# Generated by innovus_enablement/scripts/gen_fakeram.py: abstract 128x116 SRAM.
# Geometry is an assumption (see script header), not PDK data.
VERSION 5.8 ;
BUSBITCHARS "[]" ;
DIVIDERCHAR "/" ;

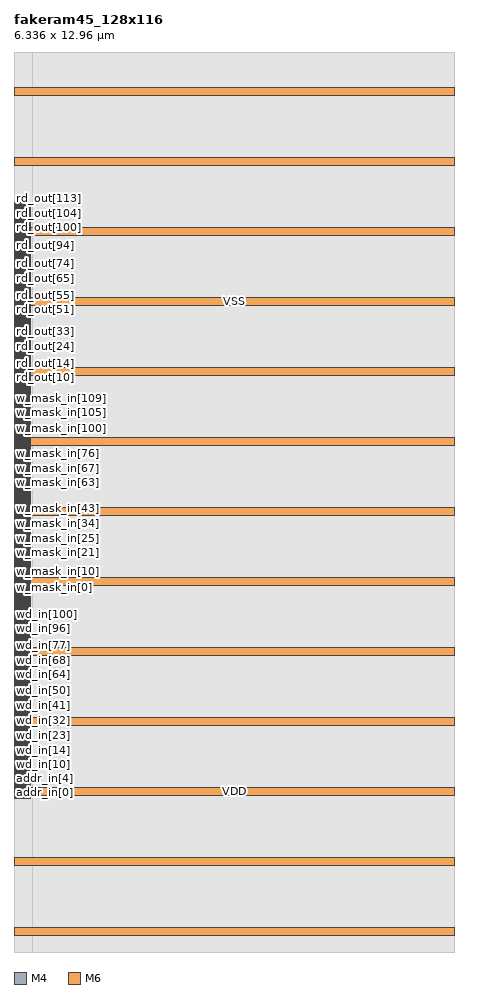
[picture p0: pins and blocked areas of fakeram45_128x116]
MACRO fakeram45_128x116
  CLASS BLOCK ;
  FOREIGN fakeram45_128x116 0 0 ;
  ORIGIN 0 0 ;
  SIZE 6.3360 BY 12.9600 ;
  SYMMETRY X Y R90 ;
  PIN clk
    DIRECTION INPUT ;
    USE CLOCK ;
    PORT
      LAYER M4 ;
        RECT 0 2.2140 0.2400 2.2260 ;
    END
  END clk
  PIN ce_in
    DIRECTION INPUT ;
    USE SIGNAL ;
    PORT
      LAYER M4 ;
        RECT 0 2.2380 0.2400 2.2500 ;
    END
  END ce_in
  PIN we_in
    DIRECTION INPUT ;
    USE SIGNAL ;
    PORT
      LAYER M4 ;
        RECT 0 2.2620 0.2400 2.2740 ;
    END
  END we_in
  PIN addr_in[0]
    DIRECTION INPUT ;
    USE SIGNAL ;
    PORT
      LAYER M4 ;
        RECT 0 2.2860 0.2400 2.2980 ;
    END
  END addr_in[0]
  PIN addr_in[1]
    DIRECTION INPUT ;
    USE SIGNAL ;
    PORT
      LAYER M4 ;
        RECT 0 2.3100 0.2400 2.3220 ;
    END
  END addr_in[1]
  PIN addr_in[2]
    DIRECTION INPUT ;
    USE SIGNAL ;
    PORT
      LAYER M4 ;
        RECT 0 2.3340 0.2400 2.3460 ;
    END
  END addr_in[2]
  PIN addr_in[3]
    DIRECTION INPUT ;
    USE SIGNAL ;
    PORT
      LAYER M4 ;
        RECT 0 2.3580 0.2400 2.3700 ;
    END
  END addr_in[3]
  PIN addr_in[4]
    DIRECTION INPUT ;
    USE SIGNAL ;
    PORT
      LAYER M4 ;
        RECT 0 2.3820 0.2400 2.3940 ;
    END
  END addr_in[4]
  PIN addr_in[5]
    DIRECTION INPUT ;
    USE SIGNAL ;
    PORT
      LAYER M4 ;
        RECT 0 2.4060 0.2400 2.4180 ;
    END
  END addr_in[5]
  PIN addr_in[6]
    DIRECTION INPUT ;
    USE SIGNAL ;
    PORT
      LAYER M4 ;
        RECT 0 2.4300 0.2400 2.4420 ;
    END
  END addr_in[6]
  PIN wd_in[0]
    DIRECTION INPUT ;
    USE SIGNAL ;
    PORT
      LAYER M4 ;
        RECT 0 2.4540 0.2400 2.4660 ;
    END
  END wd_in[0]
  PIN wd_in[1]
    DIRECTION INPUT ;
    USE SIGNAL ;
    PORT
      LAYER M4 ;
        RECT 0 2.4780 0.2400 2.4900 ;
    END
  END wd_in[1]
  PIN wd_in[2]
    DIRECTION INPUT ;
    USE SIGNAL ;
    PORT
      LAYER M4 ;
        RECT 0 2.5020 0.2400 2.5140 ;
    END
  END wd_in[2]
  PIN wd_in[3]
    DIRECTION INPUT ;
    USE SIGNAL ;
    PORT
      LAYER M4 ;
        RECT 0 2.5260 0.2400 2.5380 ;
    END
  END wd_in[3]
  PIN wd_in[4]
    DIRECTION INPUT ;
    USE SIGNAL ;
    PORT
      LAYER M4 ;
        RECT 0 2.5500 0.2400 2.5620 ;
    END
  END wd_in[4]
  PIN wd_in[5]
    DIRECTION INPUT ;
    USE SIGNAL ;
    PORT
      LAYER M4 ;
        RECT 0 2.5740 0.2400 2.5860 ;
    END
  END wd_in[5]
  PIN wd_in[6]
    DIRECTION INPUT ;
    USE SIGNAL ;
    PORT
      LAYER M4 ;
        RECT 0 2.5980 0.2400 2.6100 ;
    END
  END wd_in[6]
  PIN wd_in[7]
    DIRECTION INPUT ;
    USE SIGNAL ;
    PORT
      LAYER M4 ;
        RECT 0 2.6220 0.2400 2.6340 ;
    END
  END wd_in[7]
  PIN wd_in[8]
    DIRECTION INPUT ;
    USE SIGNAL ;
    PORT
      LAYER M4 ;
        RECT 0 2.6460 0.2400 2.6580 ;
    END
  END wd_in[8]
  PIN wd_in[9]
    DIRECTION INPUT ;
    USE SIGNAL ;
    PORT
      LAYER M4 ;
        RECT 0 2.6700 0.2400 2.6820 ;
    END
  END wd_in[9]
  PIN wd_in[10]
    DIRECTION INPUT ;
    USE SIGNAL ;
    PORT
      LAYER M4 ;
        RECT 0 2.6940 0.2400 2.7060 ;
    END
  END wd_in[10]
  PIN wd_in[11]
    DIRECTION INPUT ;
    USE SIGNAL ;
    PORT
      LAYER M4 ;
        RECT 0 2.7180 0.2400 2.7300 ;
    END
  END wd_in[11]
  PIN wd_in[12]
    DIRECTION INPUT ;
    USE SIGNAL ;
    PORT
      LAYER M4 ;
        RECT 0 2.7420 0.2400 2.7540 ;
    END
  END wd_in[12]
  PIN wd_in[13]
    DIRECTION INPUT ;
    USE SIGNAL ;
    PORT
      LAYER M4 ;
        RECT 0 2.7660 0.2400 2.7780 ;
    END
  END wd_in[13]
  PIN wd_in[14]
    DIRECTION INPUT ;
    USE SIGNAL ;
    PORT
      LAYER M4 ;
        RECT 0 2.7900 0.2400 2.8020 ;
    END
  END wd_in[14]
  PIN wd_in[15]
    DIRECTION INPUT ;
    USE SIGNAL ;
    PORT
      LAYER M4 ;
        RECT 0 2.8140 0.2400 2.8260 ;
    END
  END wd_in[15]
  PIN wd_in[16]
    DIRECTION INPUT ;
    USE SIGNAL ;
    PORT
      LAYER M4 ;
        RECT 0 2.8380 0.2400 2.8500 ;
    END
  END wd_in[16]
  PIN wd_in[17]
    DIRECTION INPUT ;
    USE SIGNAL ;
    PORT
      LAYER M4 ;
        RECT 0 2.8620 0.2400 2.8740 ;
    END
  END wd_in[17]
  PIN wd_in[18]
    DIRECTION INPUT ;
    USE SIGNAL ;
    PORT
      LAYER M4 ;
        RECT 0 2.8860 0.2400 2.8980 ;
    END
  END wd_in[18]
  PIN wd_in[19]
    DIRECTION INPUT ;
    USE SIGNAL ;
    PORT
      LAYER M4 ;
        RECT 0 2.9100 0.2400 2.9220 ;
    END
  END wd_in[19]
  PIN wd_in[20]
    DIRECTION INPUT ;
    USE SIGNAL ;
    PORT
      LAYER M4 ;
        RECT 0 2.9340 0.2400 2.9460 ;
    END
  END wd_in[20]
  PIN wd_in[21]
    DIRECTION INPUT ;
    USE SIGNAL ;
    PORT
      LAYER M4 ;
        RECT 0 2.9580 0.2400 2.9700 ;
    END
  END wd_in[21]
  PIN wd_in[22]
    DIRECTION INPUT ;
    USE SIGNAL ;
    PORT
      LAYER M4 ;
        RECT 0 2.9820 0.2400 2.9940 ;
    END
  END wd_in[22]
  PIN wd_in[23]
    DIRECTION INPUT ;
    USE SIGNAL ;
    PORT
      LAYER M4 ;
        RECT 0 3.0060 0.2400 3.0180 ;
    END
  END wd_in[23]
  PIN wd_in[24]
    DIRECTION INPUT ;
    USE SIGNAL ;
    PORT
      LAYER M4 ;
        RECT 0 3.0300 0.2400 3.0420 ;
    END
  END wd_in[24]
  PIN wd_in[25]
    DIRECTION INPUT ;
    USE SIGNAL ;
    PORT
      LAYER M4 ;
        RECT 0 3.0540 0.2400 3.0660 ;
    END
  END wd_in[25]
  PIN wd_in[26]
    DIRECTION INPUT ;
    USE SIGNAL ;
    PORT
      LAYER M4 ;
        RECT 0 3.0780 0.2400 3.0900 ;
    END
  END wd_in[26]
  PIN wd_in[27]
    DIRECTION INPUT ;
    USE SIGNAL ;
    PORT
      LAYER M4 ;
        RECT 0 3.1020 0.2400 3.1140 ;
    END
  END wd_in[27]
  PIN wd_in[28]
    DIRECTION INPUT ;
    USE SIGNAL ;
    PORT
      LAYER M4 ;
        RECT 0 3.1260 0.2400 3.1380 ;
    END
  END wd_in[28]
  PIN wd_in[29]
    DIRECTION INPUT ;
    USE SIGNAL ;
    PORT
      LAYER M4 ;
        RECT 0 3.1500 0.2400 3.1620 ;
    END
  END wd_in[29]
  PIN wd_in[30]
    DIRECTION INPUT ;
    USE SIGNAL ;
    PORT
      LAYER M4 ;
        RECT 0 3.1740 0.2400 3.1860 ;
    END
  END wd_in[30]
  PIN wd_in[31]
    DIRECTION INPUT ;
    USE SIGNAL ;
    PORT
      LAYER M4 ;
        RECT 0 3.1980 0.2400 3.2100 ;
    END
  END wd_in[31]
  PIN wd_in[32]
    DIRECTION INPUT ;
    USE SIGNAL ;
    PORT
      LAYER M4 ;
        RECT 0 3.2220 0.2400 3.2340 ;
    END
  END wd_in[32]
  PIN wd_in[33]
    DIRECTION INPUT ;
    USE SIGNAL ;
    PORT
      LAYER M4 ;
        RECT 0 3.2460 0.2400 3.2580 ;
    END
  END wd_in[33]
  PIN wd_in[34]
    DIRECTION INPUT ;
    USE SIGNAL ;
    PORT
      LAYER M4 ;
        RECT 0 3.2700 0.2400 3.2820 ;
    END
  END wd_in[34]
  PIN wd_in[35]
    DIRECTION INPUT ;
    USE SIGNAL ;
    PORT
      LAYER M4 ;
        RECT 0 3.2940 0.2400 3.3060 ;
    END
  END wd_in[35]
  PIN wd_in[36]
    DIRECTION INPUT ;
    USE SIGNAL ;
    PORT
      LAYER M4 ;
        RECT 0 3.3180 0.2400 3.3300 ;
    END
  END wd_in[36]
  PIN wd_in[37]
    DIRECTION INPUT ;
    USE SIGNAL ;
    PORT
      LAYER M4 ;
        RECT 0 3.3420 0.2400 3.3540 ;
    END
  END wd_in[37]
  PIN wd_in[38]
    DIRECTION INPUT ;
    USE SIGNAL ;
    PORT
      LAYER M4 ;
        RECT 0 3.3660 0.2400 3.3780 ;
    END
  END wd_in[38]
  PIN wd_in[39]
    DIRECTION INPUT ;
    USE SIGNAL ;
    PORT
      LAYER M4 ;
        RECT 0 3.3900 0.2400 3.4020 ;
    END
  END wd_in[39]
  PIN wd_in[40]
    DIRECTION INPUT ;
    USE SIGNAL ;
    PORT
      LAYER M4 ;
        RECT 0 3.4140 0.2400 3.4260 ;
    END
  END wd_in[40]
  PIN wd_in[41]
    DIRECTION INPUT ;
    USE SIGNAL ;
    PORT
      LAYER M4 ;
        RECT 0 3.4380 0.2400 3.4500 ;
    END
  END wd_in[41]
  PIN wd_in[42]
    DIRECTION INPUT ;
    USE SIGNAL ;
    PORT
      LAYER M4 ;
        RECT 0 3.4620 0.2400 3.4740 ;
    END
  END wd_in[42]
  PIN wd_in[43]
    DIRECTION INPUT ;
    USE SIGNAL ;
    PORT
      LAYER M4 ;
        RECT 0 3.4860 0.2400 3.4980 ;
    END
  END wd_in[43]
  PIN wd_in[44]
    DIRECTION INPUT ;
    USE SIGNAL ;
    PORT
      LAYER M4 ;
        RECT 0 3.5100 0.2400 3.5220 ;
    END
  END wd_in[44]
  PIN wd_in[45]
    DIRECTION INPUT ;
    USE SIGNAL ;
    PORT
      LAYER M4 ;
        RECT 0 3.5340 0.2400 3.5460 ;
    END
  END wd_in[45]
  PIN wd_in[46]
    DIRECTION INPUT ;
    USE SIGNAL ;
    PORT
      LAYER M4 ;
        RECT 0 3.5580 0.2400 3.5700 ;
    END
  END wd_in[46]
  PIN wd_in[47]
    DIRECTION INPUT ;
    USE SIGNAL ;
    PORT
      LAYER M4 ;
        RECT 0 3.5820 0.2400 3.5940 ;
    END
  END wd_in[47]
  PIN wd_in[48]
    DIRECTION INPUT ;
    USE SIGNAL ;
    PORT
      LAYER M4 ;
        RECT 0 3.6060 0.2400 3.6180 ;
    END
  END wd_in[48]
  PIN wd_in[49]
    DIRECTION INPUT ;
    USE SIGNAL ;
    PORT
      LAYER M4 ;
        RECT 0 3.6300 0.2400 3.6420 ;
    END
  END wd_in[49]
  PIN wd_in[50]
    DIRECTION INPUT ;
    USE SIGNAL ;
    PORT
      LAYER M4 ;
        RECT 0 3.6540 0.2400 3.6660 ;
    END
  END wd_in[50]
  PIN wd_in[51]
    DIRECTION INPUT ;
    USE SIGNAL ;
    PORT
      LAYER M4 ;
        RECT 0 3.6780 0.2400 3.6900 ;
    END
  END wd_in[51]
  PIN wd_in[52]
    DIRECTION INPUT ;
    USE SIGNAL ;
    PORT
      LAYER M4 ;
        RECT 0 3.7020 0.2400 3.7140 ;
    END
  END wd_in[52]
  PIN wd_in[53]
    DIRECTION INPUT ;
    USE SIGNAL ;
    PORT
      LAYER M4 ;
        RECT 0 3.7260 0.2400 3.7380 ;
    END
  END wd_in[53]
  PIN wd_in[54]
    DIRECTION INPUT ;
    USE SIGNAL ;
    PORT
      LAYER M4 ;
        RECT 0 3.7500 0.2400 3.7620 ;
    END
  END wd_in[54]
  PIN wd_in[55]
    DIRECTION INPUT ;
    USE SIGNAL ;
    PORT
      LAYER M4 ;
        RECT 0 3.7740 0.2400 3.7860 ;
    END
  END wd_in[55]
  PIN wd_in[56]
    DIRECTION INPUT ;
    USE SIGNAL ;
    PORT
      LAYER M4 ;
        RECT 0 3.7980 0.2400 3.8100 ;
    END
  END wd_in[56]
  PIN wd_in[57]
    DIRECTION INPUT ;
    USE SIGNAL ;
    PORT
      LAYER M4 ;
        RECT 0 3.8220 0.2400 3.8340 ;
    END
  END wd_in[57]
  PIN wd_in[58]
    DIRECTION INPUT ;
    USE SIGNAL ;
    PORT
      LAYER M4 ;
        RECT 0 3.8460 0.2400 3.8580 ;
    END
  END wd_in[58]
  PIN wd_in[59]
    DIRECTION INPUT ;
    USE SIGNAL ;
    PORT
      LAYER M4 ;
        RECT 0 3.8700 0.2400 3.8820 ;
    END
  END wd_in[59]
  PIN wd_in[60]
    DIRECTION INPUT ;
    USE SIGNAL ;
    PORT
      LAYER M4 ;
        RECT 0 3.8940 0.2400 3.9060 ;
    END
  END wd_in[60]
  PIN wd_in[61]
    DIRECTION INPUT ;
    USE SIGNAL ;
    PORT
      LAYER M4 ;
        RECT 0 3.9180 0.2400 3.9300 ;
    END
  END wd_in[61]
  PIN wd_in[62]
    DIRECTION INPUT ;
    USE SIGNAL ;
    PORT
      LAYER M4 ;
        RECT 0 3.9420 0.2400 3.9540 ;
    END
  END wd_in[62]
  PIN wd_in[63]
    DIRECTION INPUT ;
    USE SIGNAL ;
    PORT
      LAYER M4 ;
        RECT 0 3.9660 0.2400 3.9780 ;
    END
  END wd_in[63]
  PIN wd_in[64]
    DIRECTION INPUT ;
    USE SIGNAL ;
    PORT
      LAYER M4 ;
        RECT 0 3.9900 0.2400 4.0020 ;
    END
  END wd_in[64]
  PIN wd_in[65]
    DIRECTION INPUT ;
    USE SIGNAL ;
    PORT
      LAYER M4 ;
        RECT 0 4.0140 0.2400 4.0260 ;
    END
  END wd_in[65]
  PIN wd_in[66]
    DIRECTION INPUT ;
    USE SIGNAL ;
    PORT
      LAYER M4 ;
        RECT 0 4.0380 0.2400 4.0500 ;
    END
  END wd_in[66]
  PIN wd_in[67]
    DIRECTION INPUT ;
    USE SIGNAL ;
    PORT
      LAYER M4 ;
        RECT 0 4.0620 0.2400 4.0740 ;
    END
  END wd_in[67]
  PIN wd_in[68]
    DIRECTION INPUT ;
    USE SIGNAL ;
    PORT
      LAYER M4 ;
        RECT 0 4.0860 0.2400 4.0980 ;
    END
  END wd_in[68]
  PIN wd_in[69]
    DIRECTION INPUT ;
    USE SIGNAL ;
    PORT
      LAYER M4 ;
        RECT 0 4.1100 0.2400 4.1220 ;
    END
  END wd_in[69]
  PIN wd_in[70]
    DIRECTION INPUT ;
    USE SIGNAL ;
    PORT
      LAYER M4 ;
        RECT 0 4.1340 0.2400 4.1460 ;
    END
  END wd_in[70]
  PIN wd_in[71]
    DIRECTION INPUT ;
    USE SIGNAL ;
    PORT
      LAYER M4 ;
        RECT 0 4.1580 0.2400 4.1700 ;
    END
  END wd_in[71]
  PIN wd_in[72]
    DIRECTION INPUT ;
    USE SIGNAL ;
    PORT
      LAYER M4 ;
        RECT 0 4.1820 0.2400 4.1940 ;
    END
  END wd_in[72]
  PIN wd_in[73]
    DIRECTION INPUT ;
    USE SIGNAL ;
    PORT
      LAYER M4 ;
        RECT 0 4.2060 0.2400 4.2180 ;
    END
  END wd_in[73]
  PIN wd_in[74]
    DIRECTION INPUT ;
    USE SIGNAL ;
    PORT
      LAYER M4 ;
        RECT 0 4.2300 0.2400 4.2420 ;
    END
  END wd_in[74]
  PIN wd_in[75]
    DIRECTION INPUT ;
    USE SIGNAL ;
    PORT
      LAYER M4 ;
        RECT 0 4.2540 0.2400 4.2660 ;
    END
  END wd_in[75]
  PIN wd_in[76]
    DIRECTION INPUT ;
    USE SIGNAL ;
    PORT
      LAYER M4 ;
        RECT 0 4.2780 0.2400 4.2900 ;
    END
  END wd_in[76]
  PIN wd_in[77]
    DIRECTION INPUT ;
    USE SIGNAL ;
    PORT
      LAYER M4 ;
        RECT 0 4.3020 0.2400 4.3140 ;
    END
  END wd_in[77]
  PIN wd_in[78]
    DIRECTION INPUT ;
    USE SIGNAL ;
    PORT
      LAYER M4 ;
        RECT 0 4.3260 0.2400 4.3380 ;
    END
  END wd_in[78]
  PIN wd_in[79]
    DIRECTION INPUT ;
    USE SIGNAL ;
    PORT
      LAYER M4 ;
        RECT 0 4.3500 0.2400 4.3620 ;
    END
  END wd_in[79]
  PIN wd_in[80]
    DIRECTION INPUT ;
    USE SIGNAL ;
    PORT
      LAYER M4 ;
        RECT 0 4.3740 0.2400 4.3860 ;
    END
  END wd_in[80]
  PIN wd_in[81]
    DIRECTION INPUT ;
    USE SIGNAL ;
    PORT
      LAYER M4 ;
        RECT 0 4.3980 0.2400 4.4100 ;
    END
  END wd_in[81]
  PIN wd_in[82]
    DIRECTION INPUT ;
    USE SIGNAL ;
    PORT
      LAYER M4 ;
        RECT 0 4.4220 0.2400 4.4340 ;
    END
  END wd_in[82]
  PIN wd_in[83]
    DIRECTION INPUT ;
    USE SIGNAL ;
    PORT
      LAYER M4 ;
        RECT 0 4.4460 0.2400 4.4580 ;
    END
  END wd_in[83]
  PIN wd_in[84]
    DIRECTION INPUT ;
    USE SIGNAL ;
    PORT
      LAYER M4 ;
        RECT 0 4.4700 0.2400 4.4820 ;
    END
  END wd_in[84]
  PIN wd_in[85]
    DIRECTION INPUT ;
    USE SIGNAL ;
    PORT
      LAYER M4 ;
        RECT 0 4.4940 0.2400 4.5060 ;
    END
  END wd_in[85]
  PIN wd_in[86]
    DIRECTION INPUT ;
    USE SIGNAL ;
    PORT
      LAYER M4 ;
        RECT 0 4.5180 0.2400 4.5300 ;
    END
  END wd_in[86]
  PIN wd_in[87]
    DIRECTION INPUT ;
    USE SIGNAL ;
    PORT
      LAYER M4 ;
        RECT 0 4.5420 0.2400 4.5540 ;
    END
  END wd_in[87]
  PIN wd_in[88]
    DIRECTION INPUT ;
    USE SIGNAL ;
    PORT
      LAYER M4 ;
        RECT 0 4.5660 0.2400 4.5780 ;
    END
  END wd_in[88]
  PIN wd_in[89]
    DIRECTION INPUT ;
    USE SIGNAL ;
    PORT
      LAYER M4 ;
        RECT 0 4.5900 0.2400 4.6020 ;
    END
  END wd_in[89]
  PIN wd_in[90]
    DIRECTION INPUT ;
    USE SIGNAL ;
    PORT
      LAYER M4 ;
        RECT 0 4.6140 0.2400 4.6260 ;
    END
  END wd_in[90]
  PIN wd_in[91]
    DIRECTION INPUT ;
    USE SIGNAL ;
    PORT
      LAYER M4 ;
        RECT 0 4.6380 0.2400 4.6500 ;
    END
  END wd_in[91]
  PIN wd_in[92]
    DIRECTION INPUT ;
    USE SIGNAL ;
    PORT
      LAYER M4 ;
        RECT 0 4.6620 0.2400 4.6740 ;
    END
  END wd_in[92]
  PIN wd_in[93]
    DIRECTION INPUT ;
    USE SIGNAL ;
    PORT
      LAYER M4 ;
        RECT 0 4.6860 0.2400 4.6980 ;
    END
  END wd_in[93]
  PIN wd_in[94]
    DIRECTION INPUT ;
    USE SIGNAL ;
    PORT
      LAYER M4 ;
        RECT 0 4.7100 0.2400 4.7220 ;
    END
  END wd_in[94]
  PIN wd_in[95]
    DIRECTION INPUT ;
    USE SIGNAL ;
    PORT
      LAYER M4 ;
        RECT 0 4.7340 0.2400 4.7460 ;
    END
  END wd_in[95]
  PIN wd_in[96]
    DIRECTION INPUT ;
    USE SIGNAL ;
    PORT
      LAYER M4 ;
        RECT 0 4.7580 0.2400 4.7700 ;
    END
  END wd_in[96]
  PIN wd_in[97]
    DIRECTION INPUT ;
    USE SIGNAL ;
    PORT
      LAYER M4 ;
        RECT 0 4.7820 0.2400 4.7940 ;
    END
  END wd_in[97]
  PIN wd_in[98]
    DIRECTION INPUT ;
    USE SIGNAL ;
    PORT
      LAYER M4 ;
        RECT 0 4.8060 0.2400 4.8180 ;
    END
  END wd_in[98]
  PIN wd_in[99]
    DIRECTION INPUT ;
    USE SIGNAL ;
    PORT
      LAYER M4 ;
        RECT 0 4.8300 0.2400 4.8420 ;
    END
  END wd_in[99]
  PIN wd_in[100]
    DIRECTION INPUT ;
    USE SIGNAL ;
    PORT
      LAYER M4 ;
        RECT 0 4.8540 0.2400 4.8660 ;
    END
  END wd_in[100]
  PIN wd_in[101]
    DIRECTION INPUT ;
    USE SIGNAL ;
    PORT
      LAYER M4 ;
        RECT 0 4.8780 0.2400 4.8900 ;
    END
  END wd_in[101]
  PIN wd_in[102]
    DIRECTION INPUT ;
    USE SIGNAL ;
    PORT
      LAYER M4 ;
        RECT 0 4.9020 0.2400 4.9140 ;
    END
  END wd_in[102]
  PIN wd_in[103]
    DIRECTION INPUT ;
    USE SIGNAL ;
    PORT
      LAYER M4 ;
        RECT 0 4.9260 0.2400 4.9380 ;
    END
  END wd_in[103]
  PIN wd_in[104]
    DIRECTION INPUT ;
    USE SIGNAL ;
    PORT
      LAYER M4 ;
        RECT 0 4.9500 0.2400 4.9620 ;
    END
  END wd_in[104]
  PIN wd_in[105]
    DIRECTION INPUT ;
    USE SIGNAL ;
    PORT
      LAYER M4 ;
        RECT 0 4.9740 0.2400 4.9860 ;
    END
  END wd_in[105]
  PIN wd_in[106]
    DIRECTION INPUT ;
    USE SIGNAL ;
    PORT
      LAYER M4 ;
        RECT 0 4.9980 0.2400 5.0100 ;
    END
  END wd_in[106]
  PIN wd_in[107]
    DIRECTION INPUT ;
    USE SIGNAL ;
    PORT
      LAYER M4 ;
        RECT 0 5.0220 0.2400 5.0340 ;
    END
  END wd_in[107]
  PIN wd_in[108]
    DIRECTION INPUT ;
    USE SIGNAL ;
    PORT
      LAYER M4 ;
        RECT 0 5.0460 0.2400 5.0580 ;
    END
  END wd_in[108]
  PIN wd_in[109]
    DIRECTION INPUT ;
    USE SIGNAL ;
    PORT
      LAYER M4 ;
        RECT 0 5.0700 0.2400 5.0820 ;
    END
  END wd_in[109]
  PIN wd_in[110]
    DIRECTION INPUT ;
    USE SIGNAL ;
    PORT
      LAYER M4 ;
        RECT 0 5.0940 0.2400 5.1060 ;
    END
  END wd_in[110]
  PIN wd_in[111]
    DIRECTION INPUT ;
    USE SIGNAL ;
    PORT
      LAYER M4 ;
        RECT 0 5.1180 0.2400 5.1300 ;
    END
  END wd_in[111]
  PIN wd_in[112]
    DIRECTION INPUT ;
    USE SIGNAL ;
    PORT
      LAYER M4 ;
        RECT 0 5.1420 0.2400 5.1540 ;
    END
  END wd_in[112]
  PIN wd_in[113]
    DIRECTION INPUT ;
    USE SIGNAL ;
    PORT
      LAYER M4 ;
        RECT 0 5.1660 0.2400 5.1780 ;
    END
  END wd_in[113]
  PIN wd_in[114]
    DIRECTION INPUT ;
    USE SIGNAL ;
    PORT
      LAYER M4 ;
        RECT 0 5.1900 0.2400 5.2020 ;
    END
  END wd_in[114]
  PIN wd_in[115]
    DIRECTION INPUT ;
    USE SIGNAL ;
    PORT
      LAYER M4 ;
        RECT 0 5.2140 0.2400 5.2260 ;
    END
  END wd_in[115]
  PIN w_mask_in[0]
    DIRECTION INPUT ;
    USE SIGNAL ;
    PORT
      LAYER M4 ;
        RECT 0 5.2380 0.2400 5.2500 ;
    END
  END w_mask_in[0]
  PIN w_mask_in[1]
    DIRECTION INPUT ;
    USE SIGNAL ;
    PORT
      LAYER M4 ;
        RECT 0 5.2620 0.2400 5.2740 ;
    END
  END w_mask_in[1]
  PIN w_mask_in[2]
    DIRECTION INPUT ;
    USE SIGNAL ;
    PORT
      LAYER M4 ;
        RECT 0 5.2860 0.2400 5.2980 ;
    END
  END w_mask_in[2]
  PIN w_mask_in[3]
    DIRECTION INPUT ;
    USE SIGNAL ;
    PORT
      LAYER M4 ;
        RECT 0 5.3100 0.2400 5.3220 ;
    END
  END w_mask_in[3]
  PIN w_mask_in[4]
    DIRECTION INPUT ;
    USE SIGNAL ;
    PORT
      LAYER M4 ;
        RECT 0 5.3340 0.2400 5.3460 ;
    END
  END w_mask_in[4]
  PIN w_mask_in[5]
    DIRECTION INPUT ;
    USE SIGNAL ;
    PORT
      LAYER M4 ;
        RECT 0 5.3580 0.2400 5.3700 ;
    END
  END w_mask_in[5]
  PIN w_mask_in[6]
    DIRECTION INPUT ;
    USE SIGNAL ;
    PORT
      LAYER M4 ;
        RECT 0 5.3820 0.2400 5.3940 ;
    END
  END w_mask_in[6]
  PIN w_mask_in[7]
    DIRECTION INPUT ;
    USE SIGNAL ;
    PORT
      LAYER M4 ;
        RECT 0 5.4060 0.2400 5.4180 ;
    END
  END w_mask_in[7]
  PIN w_mask_in[8]
    DIRECTION INPUT ;
    USE SIGNAL ;
    PORT
      LAYER M4 ;
        RECT 0 5.4300 0.2400 5.4420 ;
    END
  END w_mask_in[8]
  PIN w_mask_in[9]
    DIRECTION INPUT ;
    USE SIGNAL ;
    PORT
      LAYER M4 ;
        RECT 0 5.4540 0.2400 5.4660 ;
    END
  END w_mask_in[9]
  PIN w_mask_in[10]
    DIRECTION INPUT ;
    USE SIGNAL ;
    PORT
      LAYER M4 ;
        RECT 0 5.4780 0.2400 5.4900 ;
    END
  END w_mask_in[10]
  PIN w_mask_in[11]
    DIRECTION INPUT ;
    USE SIGNAL ;
    PORT
      LAYER M4 ;
        RECT 0 5.5020 0.2400 5.5140 ;
    END
  END w_mask_in[11]
  PIN w_mask_in[12]
    DIRECTION INPUT ;
    USE SIGNAL ;
    PORT
      LAYER M4 ;
        RECT 0 5.5260 0.2400 5.5380 ;
    END
  END w_mask_in[12]
  PIN w_mask_in[13]
    DIRECTION INPUT ;
    USE SIGNAL ;
    PORT
      LAYER M4 ;
        RECT 0 5.5500 0.2400 5.5620 ;
    END
  END w_mask_in[13]
  PIN w_mask_in[14]
    DIRECTION INPUT ;
    USE SIGNAL ;
    PORT
      LAYER M4 ;
        RECT 0 5.5740 0.2400 5.5860 ;
    END
  END w_mask_in[14]
  PIN w_mask_in[15]
    DIRECTION INPUT ;
    USE SIGNAL ;
    PORT
      LAYER M4 ;
        RECT 0 5.5980 0.2400 5.6100 ;
    END
  END w_mask_in[15]
  PIN w_mask_in[16]
    DIRECTION INPUT ;
    USE SIGNAL ;
    PORT
      LAYER M4 ;
        RECT 0 5.6220 0.2400 5.6340 ;
    END
  END w_mask_in[16]
  PIN w_mask_in[17]
    DIRECTION INPUT ;
    USE SIGNAL ;
    PORT
      LAYER M4 ;
        RECT 0 5.6460 0.2400 5.6580 ;
    END
  END w_mask_in[17]
  PIN w_mask_in[18]
    DIRECTION INPUT ;
    USE SIGNAL ;
    PORT
      LAYER M4 ;
        RECT 0 5.6700 0.2400 5.6820 ;
    END
  END w_mask_in[18]
  PIN w_mask_in[19]
    DIRECTION INPUT ;
    USE SIGNAL ;
    PORT
      LAYER M4 ;
        RECT 0 5.6940 0.2400 5.7060 ;
    END
  END w_mask_in[19]
  PIN w_mask_in[20]
    DIRECTION INPUT ;
    USE SIGNAL ;
    PORT
      LAYER M4 ;
        RECT 0 5.7180 0.2400 5.7300 ;
    END
  END w_mask_in[20]
  PIN w_mask_in[21]
    DIRECTION INPUT ;
    USE SIGNAL ;
    PORT
      LAYER M4 ;
        RECT 0 5.7420 0.2400 5.7540 ;
    END
  END w_mask_in[21]
  PIN w_mask_in[22]
    DIRECTION INPUT ;
    USE SIGNAL ;
    PORT
      LAYER M4 ;
        RECT 0 5.7660 0.2400 5.7780 ;
    END
  END w_mask_in[22]
  PIN w_mask_in[23]
    DIRECTION INPUT ;
    USE SIGNAL ;
    PORT
      LAYER M4 ;
        RECT 0 5.7900 0.2400 5.8020 ;
    END
  END w_mask_in[23]
  PIN w_mask_in[24]
    DIRECTION INPUT ;
    USE SIGNAL ;
    PORT
      LAYER M4 ;
        RECT 0 5.8140 0.2400 5.8260 ;
    END
  END w_mask_in[24]
  PIN w_mask_in[25]
    DIRECTION INPUT ;
    USE SIGNAL ;
    PORT
      LAYER M4 ;
        RECT 0 5.8380 0.2400 5.8500 ;
    END
  END w_mask_in[25]
  PIN w_mask_in[26]
    DIRECTION INPUT ;
    USE SIGNAL ;
    PORT
      LAYER M4 ;
        RECT 0 5.8620 0.2400 5.8740 ;
    END
  END w_mask_in[26]
  PIN w_mask_in[27]
    DIRECTION INPUT ;
    USE SIGNAL ;
    PORT
      LAYER M4 ;
        RECT 0 5.8860 0.2400 5.8980 ;
    END
  END w_mask_in[27]
  PIN w_mask_in[28]
    DIRECTION INPUT ;
    USE SIGNAL ;
    PORT
      LAYER M4 ;
        RECT 0 5.9100 0.2400 5.9220 ;
    END
  END w_mask_in[28]
  PIN w_mask_in[29]
    DIRECTION INPUT ;
    USE SIGNAL ;
    PORT
      LAYER M4 ;
        RECT 0 5.9340 0.2400 5.9460 ;
    END
  END w_mask_in[29]
  PIN w_mask_in[30]
    DIRECTION INPUT ;
    USE SIGNAL ;
    PORT
      LAYER M4 ;
        RECT 0 5.9580 0.2400 5.9700 ;
    END
  END w_mask_in[30]
  PIN w_mask_in[31]
    DIRECTION INPUT ;
    USE SIGNAL ;
    PORT
      LAYER M4 ;
        RECT 0 5.9820 0.2400 5.9940 ;
    END
  END w_mask_in[31]
  PIN w_mask_in[32]
    DIRECTION INPUT ;
    USE SIGNAL ;
    PORT
      LAYER M4 ;
        RECT 0 6.0060 0.2400 6.0180 ;
    END
  END w_mask_in[32]
  PIN w_mask_in[33]
    DIRECTION INPUT ;
    USE SIGNAL ;
    PORT
      LAYER M4 ;
        RECT 0 6.0300 0.2400 6.0420 ;
    END
  END w_mask_in[33]
  PIN w_mask_in[34]
    DIRECTION INPUT ;
    USE SIGNAL ;
    PORT
      LAYER M4 ;
        RECT 0 6.0540 0.2400 6.0660 ;
    END
  END w_mask_in[34]
  PIN w_mask_in[35]
    DIRECTION INPUT ;
    USE SIGNAL ;
    PORT
      LAYER M4 ;
        RECT 0 6.0780 0.2400 6.0900 ;
    END
  END w_mask_in[35]
  PIN w_mask_in[36]
    DIRECTION INPUT ;
    USE SIGNAL ;
    PORT
      LAYER M4 ;
        RECT 0 6.1020 0.2400 6.1140 ;
    END
  END w_mask_in[36]
  PIN w_mask_in[37]
    DIRECTION INPUT ;
    USE SIGNAL ;
    PORT
      LAYER M4 ;
        RECT 0 6.1260 0.2400 6.1380 ;
    END
  END w_mask_in[37]
  PIN w_mask_in[38]
    DIRECTION INPUT ;
    USE SIGNAL ;
    PORT
      LAYER M4 ;
        RECT 0 6.1500 0.2400 6.1620 ;
    END
  END w_mask_in[38]
  PIN w_mask_in[39]
    DIRECTION INPUT ;
    USE SIGNAL ;
    PORT
      LAYER M4 ;
        RECT 0 6.1740 0.2400 6.1860 ;
    END
  END w_mask_in[39]
  PIN w_mask_in[40]
    DIRECTION INPUT ;
    USE SIGNAL ;
    PORT
      LAYER M4 ;
        RECT 0 6.1980 0.2400 6.2100 ;
    END
  END w_mask_in[40]
  PIN w_mask_in[41]
    DIRECTION INPUT ;
    USE SIGNAL ;
    PORT
      LAYER M4 ;
        RECT 0 6.2220 0.2400 6.2340 ;
    END
  END w_mask_in[41]
  PIN w_mask_in[42]
    DIRECTION INPUT ;
    USE SIGNAL ;
    PORT
      LAYER M4 ;
        RECT 0 6.2460 0.2400 6.2580 ;
    END
  END w_mask_in[42]
  PIN w_mask_in[43]
    DIRECTION INPUT ;
    USE SIGNAL ;
    PORT
      LAYER M4 ;
        RECT 0 6.2700 0.2400 6.2820 ;
    END
  END w_mask_in[43]
  PIN w_mask_in[44]
    DIRECTION INPUT ;
    USE SIGNAL ;
    PORT
      LAYER M4 ;
        RECT 0 6.2940 0.2400 6.3060 ;
    END
  END w_mask_in[44]
  PIN w_mask_in[45]
    DIRECTION INPUT ;
    USE SIGNAL ;
    PORT
      LAYER M4 ;
        RECT 0 6.3180 0.2400 6.3300 ;
    END
  END w_mask_in[45]
  PIN w_mask_in[46]
    DIRECTION INPUT ;
    USE SIGNAL ;
    PORT
      LAYER M4 ;
        RECT 0 6.3420 0.2400 6.3540 ;
    END
  END w_mask_in[46]
  PIN w_mask_in[47]
    DIRECTION INPUT ;
    USE SIGNAL ;
    PORT
      LAYER M4 ;
        RECT 0 6.3660 0.2400 6.3780 ;
    END
  END w_mask_in[47]
  PIN w_mask_in[48]
    DIRECTION INPUT ;
    USE SIGNAL ;
    PORT
      LAYER M4 ;
        RECT 0 6.3900 0.2400 6.4020 ;
    END
  END w_mask_in[48]
  PIN w_mask_in[49]
    DIRECTION INPUT ;
    USE SIGNAL ;
    PORT
      LAYER M4 ;
        RECT 0 6.4140 0.2400 6.4260 ;
    END
  END w_mask_in[49]
  PIN w_mask_in[50]
    DIRECTION INPUT ;
    USE SIGNAL ;
    PORT
      LAYER M4 ;
        RECT 0 6.4380 0.2400 6.4500 ;
    END
  END w_mask_in[50]
  PIN w_mask_in[51]
    DIRECTION INPUT ;
    USE SIGNAL ;
    PORT
      LAYER M4 ;
        RECT 0 6.4620 0.2400 6.4740 ;
    END
  END w_mask_in[51]
  PIN w_mask_in[52]
    DIRECTION INPUT ;
    USE SIGNAL ;
    PORT
      LAYER M4 ;
        RECT 0 6.4860 0.2400 6.4980 ;
    END
  END w_mask_in[52]
  PIN w_mask_in[53]
    DIRECTION INPUT ;
    USE SIGNAL ;
    PORT
      LAYER M4 ;
        RECT 0 6.5100 0.2400 6.5220 ;
    END
  END w_mask_in[53]
  PIN w_mask_in[54]
    DIRECTION INPUT ;
    USE SIGNAL ;
    PORT
      LAYER M4 ;
        RECT 0 6.5340 0.2400 6.5460 ;
    END
  END w_mask_in[54]
  PIN w_mask_in[55]
    DIRECTION INPUT ;
    USE SIGNAL ;
    PORT
      LAYER M4 ;
        RECT 0 6.5580 0.2400 6.5700 ;
    END
  END w_mask_in[55]
  PIN w_mask_in[56]
    DIRECTION INPUT ;
    USE SIGNAL ;
    PORT
      LAYER M4 ;
        RECT 0 6.5820 0.2400 6.5940 ;
    END
  END w_mask_in[56]
  PIN w_mask_in[57]
    DIRECTION INPUT ;
    USE SIGNAL ;
    PORT
      LAYER M4 ;
        RECT 0 6.6060 0.2400 6.6180 ;
    END
  END w_mask_in[57]
  PIN w_mask_in[58]
    DIRECTION INPUT ;
    USE SIGNAL ;
    PORT
      LAYER M4 ;
        RECT 0 6.6300 0.2400 6.6420 ;
    END
  END w_mask_in[58]
  PIN w_mask_in[59]
    DIRECTION INPUT ;
    USE SIGNAL ;
    PORT
      LAYER M4 ;
        RECT 0 6.6540 0.2400 6.6660 ;
    END
  END w_mask_in[59]
  PIN w_mask_in[60]
    DIRECTION INPUT ;
    USE SIGNAL ;
    PORT
      LAYER M4 ;
        RECT 0 6.6780 0.2400 6.6900 ;
    END
  END w_mask_in[60]
  PIN w_mask_in[61]
    DIRECTION INPUT ;
    USE SIGNAL ;
    PORT
      LAYER M4 ;
        RECT 0 6.7020 0.2400 6.7140 ;
    END
  END w_mask_in[61]
  PIN w_mask_in[62]
    DIRECTION INPUT ;
    USE SIGNAL ;
    PORT
      LAYER M4 ;
        RECT 0 6.7260 0.2400 6.7380 ;
    END
  END w_mask_in[62]
  PIN w_mask_in[63]
    DIRECTION INPUT ;
    USE SIGNAL ;
    PORT
      LAYER M4 ;
        RECT 0 6.7500 0.2400 6.7620 ;
    END
  END w_mask_in[63]
  PIN w_mask_in[64]
    DIRECTION INPUT ;
    USE SIGNAL ;
    PORT
      LAYER M4 ;
        RECT 0 6.7740 0.2400 6.7860 ;
    END
  END w_mask_in[64]
  PIN w_mask_in[65]
    DIRECTION INPUT ;
    USE SIGNAL ;
    PORT
      LAYER M4 ;
        RECT 0 6.7980 0.2400 6.8100 ;
    END
  END w_mask_in[65]
  PIN w_mask_in[66]
    DIRECTION INPUT ;
    USE SIGNAL ;
    PORT
      LAYER M4 ;
        RECT 0 6.8220 0.2400 6.8340 ;
    END
  END w_mask_in[66]
  PIN w_mask_in[67]
    DIRECTION INPUT ;
    USE SIGNAL ;
    PORT
      LAYER M4 ;
        RECT 0 6.8460 0.2400 6.8580 ;
    END
  END w_mask_in[67]
  PIN w_mask_in[68]
    DIRECTION INPUT ;
    USE SIGNAL ;
    PORT
      LAYER M4 ;
        RECT 0 6.8700 0.2400 6.8820 ;
    END
  END w_mask_in[68]
  PIN w_mask_in[69]
    DIRECTION INPUT ;
    USE SIGNAL ;
    PORT
      LAYER M4 ;
        RECT 0 6.8940 0.2400 6.9060 ;
    END
  END w_mask_in[69]
  PIN w_mask_in[70]
    DIRECTION INPUT ;
    USE SIGNAL ;
    PORT
      LAYER M4 ;
        RECT 0 6.9180 0.2400 6.9300 ;
    END
  END w_mask_in[70]
  PIN w_mask_in[71]
    DIRECTION INPUT ;
    USE SIGNAL ;
    PORT
      LAYER M4 ;
        RECT 0 6.9420 0.2400 6.9540 ;
    END
  END w_mask_in[71]
  PIN w_mask_in[72]
    DIRECTION INPUT ;
    USE SIGNAL ;
    PORT
      LAYER M4 ;
        RECT 0 6.9660 0.2400 6.9780 ;
    END
  END w_mask_in[72]
  PIN w_mask_in[73]
    DIRECTION INPUT ;
    USE SIGNAL ;
    PORT
      LAYER M4 ;
        RECT 0 6.9900 0.2400 7.0020 ;
    END
  END w_mask_in[73]
  PIN w_mask_in[74]
    DIRECTION INPUT ;
    USE SIGNAL ;
    PORT
      LAYER M4 ;
        RECT 0 7.0140 0.2400 7.0260 ;
    END
  END w_mask_in[74]
  PIN w_mask_in[75]
    DIRECTION INPUT ;
    USE SIGNAL ;
    PORT
      LAYER M4 ;
        RECT 0 7.0380 0.2400 7.0500 ;
    END
  END w_mask_in[75]
  PIN w_mask_in[76]
    DIRECTION INPUT ;
    USE SIGNAL ;
    PORT
      LAYER M4 ;
        RECT 0 7.0620 0.2400 7.0740 ;
    END
  END w_mask_in[76]
  PIN w_mask_in[77]
    DIRECTION INPUT ;
    USE SIGNAL ;
    PORT
      LAYER M4 ;
        RECT 0 7.0860 0.2400 7.0980 ;
    END
  END w_mask_in[77]
  PIN w_mask_in[78]
    DIRECTION INPUT ;
    USE SIGNAL ;
    PORT
      LAYER M4 ;
        RECT 0 7.1100 0.2400 7.1220 ;
    END
  END w_mask_in[78]
  PIN w_mask_in[79]
    DIRECTION INPUT ;
    USE SIGNAL ;
    PORT
      LAYER M4 ;
        RECT 0 7.1340 0.2400 7.1460 ;
    END
  END w_mask_in[79]
  PIN w_mask_in[80]
    DIRECTION INPUT ;
    USE SIGNAL ;
    PORT
      LAYER M4 ;
        RECT 0 7.1580 0.2400 7.1700 ;
    END
  END w_mask_in[80]
  PIN w_mask_in[81]
    DIRECTION INPUT ;
    USE SIGNAL ;
    PORT
      LAYER M4 ;
        RECT 0 7.1820 0.2400 7.1940 ;
    END
  END w_mask_in[81]
  PIN w_mask_in[82]
    DIRECTION INPUT ;
    USE SIGNAL ;
    PORT
      LAYER M4 ;
        RECT 0 7.2060 0.2400 7.2180 ;
    END
  END w_mask_in[82]
  PIN w_mask_in[83]
    DIRECTION INPUT ;
    USE SIGNAL ;
    PORT
      LAYER M4 ;
        RECT 0 7.2300 0.2400 7.2420 ;
    END
  END w_mask_in[83]
  PIN w_mask_in[84]
    DIRECTION INPUT ;
    USE SIGNAL ;
    PORT
      LAYER M4 ;
        RECT 0 7.2540 0.2400 7.2660 ;
    END
  END w_mask_in[84]
  PIN w_mask_in[85]
    DIRECTION INPUT ;
    USE SIGNAL ;
    PORT
      LAYER M4 ;
        RECT 0 7.2780 0.2400 7.2900 ;
    END
  END w_mask_in[85]
  PIN w_mask_in[86]
    DIRECTION INPUT ;
    USE SIGNAL ;
    PORT
      LAYER M4 ;
        RECT 0 7.3020 0.2400 7.3140 ;
    END
  END w_mask_in[86]
  PIN w_mask_in[87]
    DIRECTION INPUT ;
    USE SIGNAL ;
    PORT
      LAYER M4 ;
        RECT 0 7.3260 0.2400 7.3380 ;
    END
  END w_mask_in[87]
  PIN w_mask_in[88]
    DIRECTION INPUT ;
    USE SIGNAL ;
    PORT
      LAYER M4 ;
        RECT 0 7.3500 0.2400 7.3620 ;
    END
  END w_mask_in[88]
  PIN w_mask_in[89]
    DIRECTION INPUT ;
    USE SIGNAL ;
    PORT
      LAYER M4 ;
        RECT 0 7.3740 0.2400 7.3860 ;
    END
  END w_mask_in[89]
  PIN w_mask_in[90]
    DIRECTION INPUT ;
    USE SIGNAL ;
    PORT
      LAYER M4 ;
        RECT 0 7.3980 0.2400 7.4100 ;
    END
  END w_mask_in[90]
  PIN w_mask_in[91]
    DIRECTION INPUT ;
    USE SIGNAL ;
    PORT
      LAYER M4 ;
        RECT 0 7.4220 0.2400 7.4340 ;
    END
  END w_mask_in[91]
  PIN w_mask_in[92]
    DIRECTION INPUT ;
    USE SIGNAL ;
    PORT
      LAYER M4 ;
        RECT 0 7.4460 0.2400 7.4580 ;
    END
  END w_mask_in[92]
  PIN w_mask_in[93]
    DIRECTION INPUT ;
    USE SIGNAL ;
    PORT
      LAYER M4 ;
        RECT 0 7.4700 0.2400 7.4820 ;
    END
  END w_mask_in[93]
  PIN w_mask_in[94]
    DIRECTION INPUT ;
    USE SIGNAL ;
    PORT
      LAYER M4 ;
        RECT 0 7.4940 0.2400 7.5060 ;
    END
  END w_mask_in[94]
  PIN w_mask_in[95]
    DIRECTION INPUT ;
    USE SIGNAL ;
    PORT
      LAYER M4 ;
        RECT 0 7.5180 0.2400 7.5300 ;
    END
  END w_mask_in[95]
  PIN w_mask_in[96]
    DIRECTION INPUT ;
    USE SIGNAL ;
    PORT
      LAYER M4 ;
        RECT 0 7.5420 0.2400 7.5540 ;
    END
  END w_mask_in[96]
  PIN w_mask_in[97]
    DIRECTION INPUT ;
    USE SIGNAL ;
    PORT
      LAYER M4 ;
        RECT 0 7.5660 0.2400 7.5780 ;
    END
  END w_mask_in[97]
  PIN w_mask_in[98]
    DIRECTION INPUT ;
    USE SIGNAL ;
    PORT
      LAYER M4 ;
        RECT 0 7.5900 0.2400 7.6020 ;
    END
  END w_mask_in[98]
  PIN w_mask_in[99]
    DIRECTION INPUT ;
    USE SIGNAL ;
    PORT
      LAYER M4 ;
        RECT 0 7.6140 0.2400 7.6260 ;
    END
  END w_mask_in[99]
  PIN w_mask_in[100]
    DIRECTION INPUT ;
    USE SIGNAL ;
    PORT
      LAYER M4 ;
        RECT 0 7.6380 0.2400 7.6500 ;
    END
  END w_mask_in[100]
  PIN w_mask_in[101]
    DIRECTION INPUT ;
    USE SIGNAL ;
    PORT
      LAYER M4 ;
        RECT 0 7.6620 0.2400 7.6740 ;
    END
  END w_mask_in[101]
  PIN w_mask_in[102]
    DIRECTION INPUT ;
    USE SIGNAL ;
    PORT
      LAYER M4 ;
        RECT 0 7.6860 0.2400 7.6980 ;
    END
  END w_mask_in[102]
  PIN w_mask_in[103]
    DIRECTION INPUT ;
    USE SIGNAL ;
    PORT
      LAYER M4 ;
        RECT 0 7.7100 0.2400 7.7220 ;
    END
  END w_mask_in[103]
  PIN w_mask_in[104]
    DIRECTION INPUT ;
    USE SIGNAL ;
    PORT
      LAYER M4 ;
        RECT 0 7.7340 0.2400 7.7460 ;
    END
  END w_mask_in[104]
  PIN w_mask_in[105]
    DIRECTION INPUT ;
    USE SIGNAL ;
    PORT
      LAYER M4 ;
        RECT 0 7.7580 0.2400 7.7700 ;
    END
  END w_mask_in[105]
  PIN w_mask_in[106]
    DIRECTION INPUT ;
    USE SIGNAL ;
    PORT
      LAYER M4 ;
        RECT 0 7.7820 0.2400 7.7940 ;
    END
  END w_mask_in[106]
  PIN w_mask_in[107]
    DIRECTION INPUT ;
    USE SIGNAL ;
    PORT
      LAYER M4 ;
        RECT 0 7.8060 0.2400 7.8180 ;
    END
  END w_mask_in[107]
  PIN w_mask_in[108]
    DIRECTION INPUT ;
    USE SIGNAL ;
    PORT
      LAYER M4 ;
        RECT 0 7.8300 0.2400 7.8420 ;
    END
  END w_mask_in[108]
  PIN w_mask_in[109]
    DIRECTION INPUT ;
    USE SIGNAL ;
    PORT
      LAYER M4 ;
        RECT 0 7.8540 0.2400 7.8660 ;
    END
  END w_mask_in[109]
  PIN w_mask_in[110]
    DIRECTION INPUT ;
    USE SIGNAL ;
    PORT
      LAYER M4 ;
        RECT 0 7.8780 0.2400 7.8900 ;
    END
  END w_mask_in[110]
  PIN w_mask_in[111]
    DIRECTION INPUT ;
    USE SIGNAL ;
    PORT
      LAYER M4 ;
        RECT 0 7.9020 0.2400 7.9140 ;
    END
  END w_mask_in[111]
  PIN w_mask_in[112]
    DIRECTION INPUT ;
    USE SIGNAL ;
    PORT
      LAYER M4 ;
        RECT 0 7.9260 0.2400 7.9380 ;
    END
  END w_mask_in[112]
  PIN w_mask_in[113]
    DIRECTION INPUT ;
    USE SIGNAL ;
    PORT
      LAYER M4 ;
        RECT 0 7.9500 0.2400 7.9620 ;
    END
  END w_mask_in[113]
  PIN w_mask_in[114]
    DIRECTION INPUT ;
    USE SIGNAL ;
    PORT
      LAYER M4 ;
        RECT 0 7.9740 0.2400 7.9860 ;
    END
  END w_mask_in[114]
  PIN w_mask_in[115]
    DIRECTION INPUT ;
    USE SIGNAL ;
    PORT
      LAYER M4 ;
        RECT 0 7.9980 0.2400 8.0100 ;
    END
  END w_mask_in[115]
  PIN rd_out[0]
    DIRECTION OUTPUT ;
    USE SIGNAL ;
    PORT
      LAYER M4 ;
        RECT 0 8.0220 0.2400 8.0340 ;
    END
  END rd_out[0]
  PIN rd_out[1]
    DIRECTION OUTPUT ;
    USE SIGNAL ;
    PORT
      LAYER M4 ;
        RECT 0 8.0460 0.2400 8.0580 ;
    END
  END rd_out[1]
  PIN rd_out[2]
    DIRECTION OUTPUT ;
    USE SIGNAL ;
    PORT
      LAYER M4 ;
        RECT 0 8.0700 0.2400 8.0820 ;
    END
  END rd_out[2]
  PIN rd_out[3]
    DIRECTION OUTPUT ;
    USE SIGNAL ;
    PORT
      LAYER M4 ;
        RECT 0 8.0940 0.2400 8.1060 ;
    END
  END rd_out[3]
  PIN rd_out[4]
    DIRECTION OUTPUT ;
    USE SIGNAL ;
    PORT
      LAYER M4 ;
        RECT 0 8.1180 0.2400 8.1300 ;
    END
  END rd_out[4]
  PIN rd_out[5]
    DIRECTION OUTPUT ;
    USE SIGNAL ;
    PORT
      LAYER M4 ;
        RECT 0 8.1420 0.2400 8.1540 ;
    END
  END rd_out[5]
  PIN rd_out[6]
    DIRECTION OUTPUT ;
    USE SIGNAL ;
    PORT
      LAYER M4 ;
        RECT 0 8.1660 0.2400 8.1780 ;
    END
  END rd_out[6]
  PIN rd_out[7]
    DIRECTION OUTPUT ;
    USE SIGNAL ;
    PORT
      LAYER M4 ;
        RECT 0 8.1900 0.2400 8.2020 ;
    END
  END rd_out[7]
  PIN rd_out[8]
    DIRECTION OUTPUT ;
    USE SIGNAL ;
    PORT
      LAYER M4 ;
        RECT 0 8.2140 0.2400 8.2260 ;
    END
  END rd_out[8]
  PIN rd_out[9]
    DIRECTION OUTPUT ;
    USE SIGNAL ;
    PORT
      LAYER M4 ;
        RECT 0 8.2380 0.2400 8.2500 ;
    END
  END rd_out[9]
  PIN rd_out[10]
    DIRECTION OUTPUT ;
    USE SIGNAL ;
    PORT
      LAYER M4 ;
        RECT 0 8.2620 0.2400 8.2740 ;
    END
  END rd_out[10]
  PIN rd_out[11]
    DIRECTION OUTPUT ;
    USE SIGNAL ;
    PORT
      LAYER M4 ;
        RECT 0 8.2860 0.2400 8.2980 ;
    END
  END rd_out[11]
  PIN rd_out[12]
    DIRECTION OUTPUT ;
    USE SIGNAL ;
    PORT
      LAYER M4 ;
        RECT 0 8.3100 0.2400 8.3220 ;
    END
  END rd_out[12]
  PIN rd_out[13]
    DIRECTION OUTPUT ;
    USE SIGNAL ;
    PORT
      LAYER M4 ;
        RECT 0 8.3340 0.2400 8.3460 ;
    END
  END rd_out[13]
  PIN rd_out[14]
    DIRECTION OUTPUT ;
    USE SIGNAL ;
    PORT
      LAYER M4 ;
        RECT 0 8.3580 0.2400 8.3700 ;
    END
  END rd_out[14]
  PIN rd_out[15]
    DIRECTION OUTPUT ;
    USE SIGNAL ;
    PORT
      LAYER M4 ;
        RECT 0 8.3820 0.2400 8.3940 ;
    END
  END rd_out[15]
  PIN rd_out[16]
    DIRECTION OUTPUT ;
    USE SIGNAL ;
    PORT
      LAYER M4 ;
        RECT 0 8.4060 0.2400 8.4180 ;
    END
  END rd_out[16]
  PIN rd_out[17]
    DIRECTION OUTPUT ;
    USE SIGNAL ;
    PORT
      LAYER M4 ;
        RECT 0 8.4300 0.2400 8.4420 ;
    END
  END rd_out[17]
  PIN rd_out[18]
    DIRECTION OUTPUT ;
    USE SIGNAL ;
    PORT
      LAYER M4 ;
        RECT 0 8.4540 0.2400 8.4660 ;
    END
  END rd_out[18]
  PIN rd_out[19]
    DIRECTION OUTPUT ;
    USE SIGNAL ;
    PORT
      LAYER M4 ;
        RECT 0 8.4780 0.2400 8.4900 ;
    END
  END rd_out[19]
  PIN rd_out[20]
    DIRECTION OUTPUT ;
    USE SIGNAL ;
    PORT
      LAYER M4 ;
        RECT 0 8.5020 0.2400 8.5140 ;
    END
  END rd_out[20]
  PIN rd_out[21]
    DIRECTION OUTPUT ;
    USE SIGNAL ;
    PORT
      LAYER M4 ;
        RECT 0 8.5260 0.2400 8.5380 ;
    END
  END rd_out[21]
  PIN rd_out[22]
    DIRECTION OUTPUT ;
    USE SIGNAL ;
    PORT
      LAYER M4 ;
        RECT 0 8.5500 0.2400 8.5620 ;
    END
  END rd_out[22]
  PIN rd_out[23]
    DIRECTION OUTPUT ;
    USE SIGNAL ;
    PORT
      LAYER M4 ;
        RECT 0 8.5740 0.2400 8.5860 ;
    END
  END rd_out[23]
  PIN rd_out[24]
    DIRECTION OUTPUT ;
    USE SIGNAL ;
    PORT
      LAYER M4 ;
        RECT 0 8.5980 0.2400 8.6100 ;
    END
  END rd_out[24]
  PIN rd_out[25]
    DIRECTION OUTPUT ;
    USE SIGNAL ;
    PORT
      LAYER M4 ;
        RECT 0 8.6220 0.2400 8.6340 ;
    END
  END rd_out[25]
  PIN rd_out[26]
    DIRECTION OUTPUT ;
    USE SIGNAL ;
    PORT
      LAYER M4 ;
        RECT 0 8.6460 0.2400 8.6580 ;
    END
  END rd_out[26]
  PIN rd_out[27]
    DIRECTION OUTPUT ;
    USE SIGNAL ;
    PORT
      LAYER M4 ;
        RECT 0 8.6700 0.2400 8.6820 ;
    END
  END rd_out[27]
  PIN rd_out[28]
    DIRECTION OUTPUT ;
    USE SIGNAL ;
    PORT
      LAYER M4 ;
        RECT 0 8.6940 0.2400 8.7060 ;
    END
  END rd_out[28]
  PIN rd_out[29]
    DIRECTION OUTPUT ;
    USE SIGNAL ;
    PORT
      LAYER M4 ;
        RECT 0 8.7180 0.2400 8.7300 ;
    END
  END rd_out[29]
  PIN rd_out[30]
    DIRECTION OUTPUT ;
    USE SIGNAL ;
    PORT
      LAYER M4 ;
        RECT 0 8.7420 0.2400 8.7540 ;
    END
  END rd_out[30]
  PIN rd_out[31]
    DIRECTION OUTPUT ;
    USE SIGNAL ;
    PORT
      LAYER M4 ;
        RECT 0 8.7660 0.2400 8.7780 ;
    END
  END rd_out[31]
  PIN rd_out[32]
    DIRECTION OUTPUT ;
    USE SIGNAL ;
    PORT
      LAYER M4 ;
        RECT 0 8.7900 0.2400 8.8020 ;
    END
  END rd_out[32]
  PIN rd_out[33]
    DIRECTION OUTPUT ;
    USE SIGNAL ;
    PORT
      LAYER M4 ;
        RECT 0 8.8140 0.2400 8.8260 ;
    END
  END rd_out[33]
  PIN rd_out[34]
    DIRECTION OUTPUT ;
    USE SIGNAL ;
    PORT
      LAYER M4 ;
        RECT 0 8.8380 0.2400 8.8500 ;
    END
  END rd_out[34]
  PIN rd_out[35]
    DIRECTION OUTPUT ;
    USE SIGNAL ;
    PORT
      LAYER M4 ;
        RECT 0 8.8620 0.2400 8.8740 ;
    END
  END rd_out[35]
  PIN rd_out[36]
    DIRECTION OUTPUT ;
    USE SIGNAL ;
    PORT
      LAYER M4 ;
        RECT 0 8.8860 0.2400 8.8980 ;
    END
  END rd_out[36]
  PIN rd_out[37]
    DIRECTION OUTPUT ;
    USE SIGNAL ;
    PORT
      LAYER M4 ;
        RECT 0 8.9100 0.2400 8.9220 ;
    END
  END rd_out[37]
  PIN rd_out[38]
    DIRECTION OUTPUT ;
    USE SIGNAL ;
    PORT
      LAYER M4 ;
        RECT 0 8.9340 0.2400 8.9460 ;
    END
  END rd_out[38]
  PIN rd_out[39]
    DIRECTION OUTPUT ;
    USE SIGNAL ;
    PORT
      LAYER M4 ;
        RECT 0 8.9580 0.2400 8.9700 ;
    END
  END rd_out[39]
  PIN rd_out[40]
    DIRECTION OUTPUT ;
    USE SIGNAL ;
    PORT
      LAYER M4 ;
        RECT 0 8.9820 0.2400 8.9940 ;
    END
  END rd_out[40]
  PIN rd_out[41]
    DIRECTION OUTPUT ;
    USE SIGNAL ;
    PORT
      LAYER M4 ;
        RECT 0 9.0060 0.2400 9.0180 ;
    END
  END rd_out[41]
  PIN rd_out[42]
    DIRECTION OUTPUT ;
    USE SIGNAL ;
    PORT
      LAYER M4 ;
        RECT 0 9.0300 0.2400 9.0420 ;
    END
  END rd_out[42]
  PIN rd_out[43]
    DIRECTION OUTPUT ;
    USE SIGNAL ;
    PORT
      LAYER M4 ;
        RECT 0 9.0540 0.2400 9.0660 ;
    END
  END rd_out[43]
  PIN rd_out[44]
    DIRECTION OUTPUT ;
    USE SIGNAL ;
    PORT
      LAYER M4 ;
        RECT 0 9.0780 0.2400 9.0900 ;
    END
  END rd_out[44]
  PIN rd_out[45]
    DIRECTION OUTPUT ;
    USE SIGNAL ;
    PORT
      LAYER M4 ;
        RECT 0 9.1020 0.2400 9.1140 ;
    END
  END rd_out[45]
  PIN rd_out[46]
    DIRECTION OUTPUT ;
    USE SIGNAL ;
    PORT
      LAYER M4 ;
        RECT 0 9.1260 0.2400 9.1380 ;
    END
  END rd_out[46]
  PIN rd_out[47]
    DIRECTION OUTPUT ;
    USE SIGNAL ;
    PORT
      LAYER M4 ;
        RECT 0 9.1500 0.2400 9.1620 ;
    END
  END rd_out[47]
  PIN rd_out[48]
    DIRECTION OUTPUT ;
    USE SIGNAL ;
    PORT
      LAYER M4 ;
        RECT 0 9.1740 0.2400 9.1860 ;
    END
  END rd_out[48]
  PIN rd_out[49]
    DIRECTION OUTPUT ;
    USE SIGNAL ;
    PORT
      LAYER M4 ;
        RECT 0 9.1980 0.2400 9.2100 ;
    END
  END rd_out[49]
  PIN rd_out[50]
    DIRECTION OUTPUT ;
    USE SIGNAL ;
    PORT
      LAYER M4 ;
        RECT 0 9.2220 0.2400 9.2340 ;
    END
  END rd_out[50]
  PIN rd_out[51]
    DIRECTION OUTPUT ;
    USE SIGNAL ;
    PORT
      LAYER M4 ;
        RECT 0 9.2460 0.2400 9.2580 ;
    END
  END rd_out[51]
  PIN rd_out[52]
    DIRECTION OUTPUT ;
    USE SIGNAL ;
    PORT
      LAYER M4 ;
        RECT 0 9.2700 0.2400 9.2820 ;
    END
  END rd_out[52]
  PIN rd_out[53]
    DIRECTION OUTPUT ;
    USE SIGNAL ;
    PORT
      LAYER M4 ;
        RECT 0 9.2940 0.2400 9.3060 ;
    END
  END rd_out[53]
  PIN rd_out[54]
    DIRECTION OUTPUT ;
    USE SIGNAL ;
    PORT
      LAYER M4 ;
        RECT 0 9.3180 0.2400 9.3300 ;
    END
  END rd_out[54]
  PIN rd_out[55]
    DIRECTION OUTPUT ;
    USE SIGNAL ;
    PORT
      LAYER M4 ;
        RECT 0 9.3420 0.2400 9.3540 ;
    END
  END rd_out[55]
  PIN rd_out[56]
    DIRECTION OUTPUT ;
    USE SIGNAL ;
    PORT
      LAYER M4 ;
        RECT 0 9.3660 0.2400 9.3780 ;
    END
  END rd_out[56]
  PIN rd_out[57]
    DIRECTION OUTPUT ;
    USE SIGNAL ;
    PORT
      LAYER M4 ;
        RECT 0 9.3900 0.2400 9.4020 ;
    END
  END rd_out[57]
  PIN rd_out[58]
    DIRECTION OUTPUT ;
    USE SIGNAL ;
    PORT
      LAYER M4 ;
        RECT 0 9.4140 0.2400 9.4260 ;
    END
  END rd_out[58]
  PIN rd_out[59]
    DIRECTION OUTPUT ;
    USE SIGNAL ;
    PORT
      LAYER M4 ;
        RECT 0 9.4380 0.2400 9.4500 ;
    END
  END rd_out[59]
  PIN rd_out[60]
    DIRECTION OUTPUT ;
    USE SIGNAL ;
    PORT
      LAYER M4 ;
        RECT 0 9.4620 0.2400 9.4740 ;
    END
  END rd_out[60]
  PIN rd_out[61]
    DIRECTION OUTPUT ;
    USE SIGNAL ;
    PORT
      LAYER M4 ;
        RECT 0 9.4860 0.2400 9.4980 ;
    END
  END rd_out[61]
  PIN rd_out[62]
    DIRECTION OUTPUT ;
    USE SIGNAL ;
    PORT
      LAYER M4 ;
        RECT 0 9.5100 0.2400 9.5220 ;
    END
  END rd_out[62]
  PIN rd_out[63]
    DIRECTION OUTPUT ;
    USE SIGNAL ;
    PORT
      LAYER M4 ;
        RECT 0 9.5340 0.2400 9.5460 ;
    END
  END rd_out[63]
  PIN rd_out[64]
    DIRECTION OUTPUT ;
    USE SIGNAL ;
    PORT
      LAYER M4 ;
        RECT 0 9.5580 0.2400 9.5700 ;
    END
  END rd_out[64]
  PIN rd_out[65]
    DIRECTION OUTPUT ;
    USE SIGNAL ;
    PORT
      LAYER M4 ;
        RECT 0 9.5820 0.2400 9.5940 ;
    END
  END rd_out[65]
  PIN rd_out[66]
    DIRECTION OUTPUT ;
    USE SIGNAL ;
    PORT
      LAYER M4 ;
        RECT 0 9.6060 0.2400 9.6180 ;
    END
  END rd_out[66]
  PIN rd_out[67]
    DIRECTION OUTPUT ;
    USE SIGNAL ;
    PORT
      LAYER M4 ;
        RECT 0 9.6300 0.2400 9.6420 ;
    END
  END rd_out[67]
  PIN rd_out[68]
    DIRECTION OUTPUT ;
    USE SIGNAL ;
    PORT
      LAYER M4 ;
        RECT 0 9.6540 0.2400 9.6660 ;
    END
  END rd_out[68]
  PIN rd_out[69]
    DIRECTION OUTPUT ;
    USE SIGNAL ;
    PORT
      LAYER M4 ;
        RECT 0 9.6780 0.2400 9.6900 ;
    END
  END rd_out[69]
  PIN rd_out[70]
    DIRECTION OUTPUT ;
    USE SIGNAL ;
    PORT
      LAYER M4 ;
        RECT 0 9.7020 0.2400 9.7140 ;
    END
  END rd_out[70]
  PIN rd_out[71]
    DIRECTION OUTPUT ;
    USE SIGNAL ;
    PORT
      LAYER M4 ;
        RECT 0 9.7260 0.2400 9.7380 ;
    END
  END rd_out[71]
  PIN rd_out[72]
    DIRECTION OUTPUT ;
    USE SIGNAL ;
    PORT
      LAYER M4 ;
        RECT 0 9.7500 0.2400 9.7620 ;
    END
  END rd_out[72]
  PIN rd_out[73]
    DIRECTION OUTPUT ;
    USE SIGNAL ;
    PORT
      LAYER M4 ;
        RECT 0 9.7740 0.2400 9.7860 ;
    END
  END rd_out[73]
  PIN rd_out[74]
    DIRECTION OUTPUT ;
    USE SIGNAL ;
    PORT
      LAYER M4 ;
        RECT 0 9.7980 0.2400 9.8100 ;
    END
  END rd_out[74]
  PIN rd_out[75]
    DIRECTION OUTPUT ;
    USE SIGNAL ;
    PORT
      LAYER M4 ;
        RECT 0 9.8220 0.2400 9.8340 ;
    END
  END rd_out[75]
  PIN rd_out[76]
    DIRECTION OUTPUT ;
    USE SIGNAL ;
    PORT
      LAYER M4 ;
        RECT 0 9.8460 0.2400 9.8580 ;
    END
  END rd_out[76]
  PIN rd_out[77]
    DIRECTION OUTPUT ;
    USE SIGNAL ;
    PORT
      LAYER M4 ;
        RECT 0 9.8700 0.2400 9.8820 ;
    END
  END rd_out[77]
  PIN rd_out[78]
    DIRECTION OUTPUT ;
    USE SIGNAL ;
    PORT
      LAYER M4 ;
        RECT 0 9.8940 0.2400 9.9060 ;
    END
  END rd_out[78]
  PIN rd_out[79]
    DIRECTION OUTPUT ;
    USE SIGNAL ;
    PORT
      LAYER M4 ;
        RECT 0 9.9180 0.2400 9.9300 ;
    END
  END rd_out[79]
  PIN rd_out[80]
    DIRECTION OUTPUT ;
    USE SIGNAL ;
    PORT
      LAYER M4 ;
        RECT 0 9.9420 0.2400 9.9540 ;
    END
  END rd_out[80]
  PIN rd_out[81]
    DIRECTION OUTPUT ;
    USE SIGNAL ;
    PORT
      LAYER M4 ;
        RECT 0 9.9660 0.2400 9.9780 ;
    END
  END rd_out[81]
  PIN rd_out[82]
    DIRECTION OUTPUT ;
    USE SIGNAL ;
    PORT
      LAYER M4 ;
        RECT 0 9.9900 0.2400 10.0020 ;
    END
  END rd_out[82]
  PIN rd_out[83]
    DIRECTION OUTPUT ;
    USE SIGNAL ;
    PORT
      LAYER M4 ;
        RECT 0 10.0140 0.2400 10.0260 ;
    END
  END rd_out[83]
  PIN rd_out[84]
    DIRECTION OUTPUT ;
    USE SIGNAL ;
    PORT
      LAYER M4 ;
        RECT 0 10.0380 0.2400 10.0500 ;
    END
  END rd_out[84]
  PIN rd_out[85]
    DIRECTION OUTPUT ;
    USE SIGNAL ;
    PORT
      LAYER M4 ;
        RECT 0 10.0620 0.2400 10.0740 ;
    END
  END rd_out[85]
  PIN rd_out[86]
    DIRECTION OUTPUT ;
    USE SIGNAL ;
    PORT
      LAYER M4 ;
        RECT 0 10.0860 0.2400 10.0980 ;
    END
  END rd_out[86]
  PIN rd_out[87]
    DIRECTION OUTPUT ;
    USE SIGNAL ;
    PORT
      LAYER M4 ;
        RECT 0 10.1100 0.2400 10.1220 ;
    END
  END rd_out[87]
  PIN rd_out[88]
    DIRECTION OUTPUT ;
    USE SIGNAL ;
    PORT
      LAYER M4 ;
        RECT 0 10.1340 0.2400 10.1460 ;
    END
  END rd_out[88]
  PIN rd_out[89]
    DIRECTION OUTPUT ;
    USE SIGNAL ;
    PORT
      LAYER M4 ;
        RECT 0 10.1580 0.2400 10.1700 ;
    END
  END rd_out[89]
  PIN rd_out[90]
    DIRECTION OUTPUT ;
    USE SIGNAL ;
    PORT
      LAYER M4 ;
        RECT 0 10.1820 0.2400 10.1940 ;
    END
  END rd_out[90]
  PIN rd_out[91]
    DIRECTION OUTPUT ;
    USE SIGNAL ;
    PORT
      LAYER M4 ;
        RECT 0 10.2060 0.2400 10.2180 ;
    END
  END rd_out[91]
  PIN rd_out[92]
    DIRECTION OUTPUT ;
    USE SIGNAL ;
    PORT
      LAYER M4 ;
        RECT 0 10.2300 0.2400 10.2420 ;
    END
  END rd_out[92]
  PIN rd_out[93]
    DIRECTION OUTPUT ;
    USE SIGNAL ;
    PORT
      LAYER M4 ;
        RECT 0 10.2540 0.2400 10.2660 ;
    END
  END rd_out[93]
  PIN rd_out[94]
    DIRECTION OUTPUT ;
    USE SIGNAL ;
    PORT
      LAYER M4 ;
        RECT 0 10.2780 0.2400 10.2900 ;
    END
  END rd_out[94]
  PIN rd_out[95]
    DIRECTION OUTPUT ;
    USE SIGNAL ;
    PORT
      LAYER M4 ;
        RECT 0 10.3020 0.2400 10.3140 ;
    END
  END rd_out[95]
  PIN rd_out[96]
    DIRECTION OUTPUT ;
    USE SIGNAL ;
    PORT
      LAYER M4 ;
        RECT 0 10.3260 0.2400 10.3380 ;
    END
  END rd_out[96]
  PIN rd_out[97]
    DIRECTION OUTPUT ;
    USE SIGNAL ;
    PORT
      LAYER M4 ;
        RECT 0 10.3500 0.2400 10.3620 ;
    END
  END rd_out[97]
  PIN rd_out[98]
    DIRECTION OUTPUT ;
    USE SIGNAL ;
    PORT
      LAYER M4 ;
        RECT 0 10.3740 0.2400 10.3860 ;
    END
  END rd_out[98]
  PIN rd_out[99]
    DIRECTION OUTPUT ;
    USE SIGNAL ;
    PORT
      LAYER M4 ;
        RECT 0 10.3980 0.2400 10.4100 ;
    END
  END rd_out[99]
  PIN rd_out[100]
    DIRECTION OUTPUT ;
    USE SIGNAL ;
    PORT
      LAYER M4 ;
        RECT 0 10.4220 0.2400 10.4340 ;
    END
  END rd_out[100]
  PIN rd_out[101]
    DIRECTION OUTPUT ;
    USE SIGNAL ;
    PORT
      LAYER M4 ;
        RECT 0 10.4460 0.2400 10.4580 ;
    END
  END rd_out[101]
  PIN rd_out[102]
    DIRECTION OUTPUT ;
    USE SIGNAL ;
    PORT
      LAYER M4 ;
        RECT 0 10.4700 0.2400 10.4820 ;
    END
  END rd_out[102]
  PIN rd_out[103]
    DIRECTION OUTPUT ;
    USE SIGNAL ;
    PORT
      LAYER M4 ;
        RECT 0 10.4940 0.2400 10.5060 ;
    END
  END rd_out[103]
  PIN rd_out[104]
    DIRECTION OUTPUT ;
    USE SIGNAL ;
    PORT
      LAYER M4 ;
        RECT 0 10.5180 0.2400 10.5300 ;
    END
  END rd_out[104]
  PIN rd_out[105]
    DIRECTION OUTPUT ;
    USE SIGNAL ;
    PORT
      LAYER M4 ;
        RECT 0 10.5420 0.2400 10.5540 ;
    END
  END rd_out[105]
  PIN rd_out[106]
    DIRECTION OUTPUT ;
    USE SIGNAL ;
    PORT
      LAYER M4 ;
        RECT 0 10.5660 0.2400 10.5780 ;
    END
  END rd_out[106]
  PIN rd_out[107]
    DIRECTION OUTPUT ;
    USE SIGNAL ;
    PORT
      LAYER M4 ;
        RECT 0 10.5900 0.2400 10.6020 ;
    END
  END rd_out[107]
  PIN rd_out[108]
    DIRECTION OUTPUT ;
    USE SIGNAL ;
    PORT
      LAYER M4 ;
        RECT 0 10.6140 0.2400 10.6260 ;
    END
  END rd_out[108]
  PIN rd_out[109]
    DIRECTION OUTPUT ;
    USE SIGNAL ;
    PORT
      LAYER M4 ;
        RECT 0 10.6380 0.2400 10.6500 ;
    END
  END rd_out[109]
  PIN rd_out[110]
    DIRECTION OUTPUT ;
    USE SIGNAL ;
    PORT
      LAYER M4 ;
        RECT 0 10.6620 0.2400 10.6740 ;
    END
  END rd_out[110]
  PIN rd_out[111]
    DIRECTION OUTPUT ;
    USE SIGNAL ;
    PORT
      LAYER M4 ;
        RECT 0 10.6860 0.2400 10.6980 ;
    END
  END rd_out[111]
  PIN rd_out[112]
    DIRECTION OUTPUT ;
    USE SIGNAL ;
    PORT
      LAYER M4 ;
        RECT 0 10.7100 0.2400 10.7220 ;
    END
  END rd_out[112]
  PIN rd_out[113]
    DIRECTION OUTPUT ;
    USE SIGNAL ;
    PORT
      LAYER M4 ;
        RECT 0 10.7340 0.2400 10.7460 ;
    END
  END rd_out[113]
  PIN rd_out[114]
    DIRECTION OUTPUT ;
    USE SIGNAL ;
    PORT
      LAYER M4 ;
        RECT 0 10.7580 0.2400 10.7700 ;
    END
  END rd_out[114]
  PIN rd_out[115]
    DIRECTION OUTPUT ;
    USE SIGNAL ;
    PORT
      LAYER M4 ;
        RECT 0 10.7820 0.2400 10.7940 ;
    END
  END rd_out[115]
  PIN VDD
    DIRECTION INOUT ;
    USE POWER ;
    PORT
      LAYER M6 ;
        RECT 0 0.2400 6.3360 0.3600 ;
        RECT 0 2.2560 6.3360 2.3760 ;
        RECT 0 4.2720 6.3360 4.3920 ;
        RECT 0 6.2880 6.3360 6.4080 ;
        RECT 0 8.3040 6.3360 8.4240 ;
        RECT 0 10.3200 6.3360 10.4400 ;
        RECT 0 12.3360 6.3360 12.4560 ;
    END
  END VDD
  PIN VSS
    DIRECTION INOUT ;
    USE GROUND ;
    PORT
      LAYER M6 ;
        RECT 0 1.2480 6.3360 1.3680 ;
        RECT 0 3.2640 6.3360 3.3840 ;
        RECT 0 5.2800 6.3360 5.4000 ;
        RECT 0 7.2960 6.3360 7.4160 ;
        RECT 0 9.3120 6.3360 9.4320 ;
        RECT 0 11.3280 6.3360 11.4480 ;
    END
  END VSS
  OBS
    LAYER M0 ;
      RECT 0 0 6.3360 12.9600 ;
    LAYER M1 ;
      RECT 0 0 6.3360 12.9600 ;
    LAYER M2 ;
      RECT 0 0 6.3360 12.9600 ;
    LAYER M3 ;
      RECT 0 0 6.3360 12.9600 ;
    LAYER VIA0 ;
      RECT 0 0 6.3360 12.9600 ;
    LAYER VIA1 ;
      RECT 0 0 6.3360 12.9600 ;
    LAYER VIA2 ;
      RECT 0 0 6.3360 12.9600 ;
    LAYER VIA3 ;
      RECT 0 0 6.3360 12.9600 ;
    LAYER M4 ;
      RECT 0.2640 0 6.3360 12.9600 ;
  END
END fakeram45_128x116

END LIBRARY
